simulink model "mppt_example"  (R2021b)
settings: Solver=VariableStepAuto  StartTime=0.0  StopTime=2  FixedStep=1e-5  RelTol=1e-3
libraries: spsSeriesRLCBranchLib x4, spsVoltageMeasurementLib x2, spsControlledCurrentSourceLib x1, spsCurrentMeasurementLib x1, spsDiodeLib x1, spsGroundLib x1, spsIGBTLib x1, simulink x1, spspowerguiLib x1

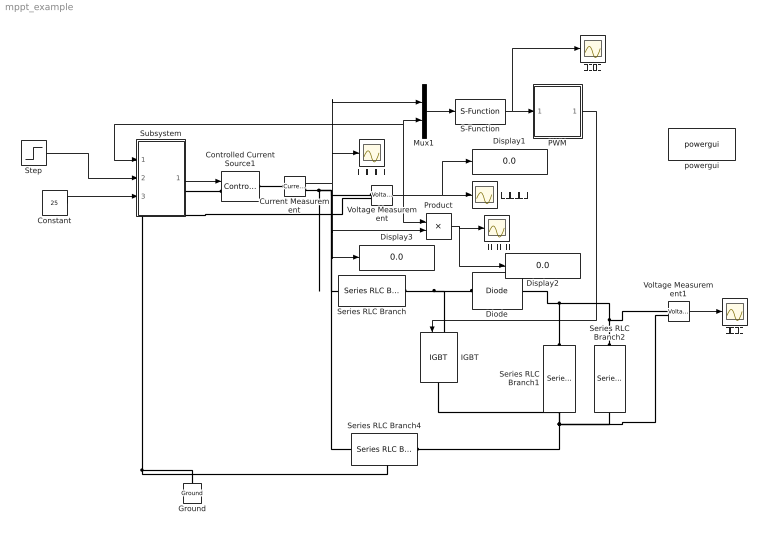
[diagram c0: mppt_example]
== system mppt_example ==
  Constant : Constant  Value=25
  Controlled Current Source1 : spsControlledCurrentSourceLib/Controlled Current Source  Initialize=on  Source_Type=AC  Amplitude=0  Phase=0  Frequency=0  Measurements=None
  Current Measurement : spsCurrentMeasurementLib/Current Measurement  PhasorSimulation=off  OutputType=Complex  PSBequivalent=0
  Diode : spsDiodeLib/Diode  Ron=0.001  Lon=0  Vf=0.8  IC=0  UseSnubber=0  Rs=500  Cs=250e-9  Measurements=off
  Display1 : Display
  Display2 : Display
  Display3 : Display
  Ground : spsGroundLib/Ground  LConnTagsString=a
  IGBT : spsIGBTLib/IGBT  Ron=0.001  Lon=0  Vf=1  Tf=1e-6  Tt=2e-6  IC=0  Rs=1e5  Cs=inf  Measurements=off
  Mux1 : Mux  Inputs=2
  PWM : Subsystem
  Product : Product
  S-Function : S-Function  FunctionName=modbusCom1  SFunctionDeploymentMode=off  EnableBusSupport=off
  Series RLC Branch : spsSeriesRLCBranchLib/Series RLC Branch  LConnTagsString=__new0  RConnTagsString=__new0  BranchType=L  Resistance=0  Inductance=1e-2  SetiL0=off  InitialCurrent=0  Capacitance=0  Setx0=off  InitialVoltage=0  Measurements=None
  Series RLC Branch1 : spsSeriesRLCBranchLib/Series RLC Branch  LConnTagsString=__new0  RConnTagsString=__new0  BranchType=C  Resistance=0  Inductance=0  SetiL0=off  InitialCurrent=0  Capacitance=3e-4  Setx0=off  InitialVoltage=0  Measurements=None
  Series RLC Branch2 : spsSeriesRLCBranchLib/Series RLC Branch  LConnTagsString=__new0  RConnTagsString=__new0  BranchType=R  Resistance=20  Inductance=0  SetiL0=off  InitialCurrent=0  Capacitance=0  Setx0=off  InitialVoltage=0  Measurements=None
  Series RLC Branch4 : spsSeriesRLCBranchLib/Series RLC Branch  LConnTagsString=__new0  RConnTagsString=__new0  BranchType=C  Resistance=0  Inductance=0  SetiL0=off  InitialCurrent=0  Capacitance=1e-4  Setx0=off  InitialVoltage=0  Measurements=None
  Step : Step  Time=0.5  Before=1000  After=1200  SampleTime=0
  Subsystem : Subsystem
  Voltage Measurement : spsVoltageMeasurementLib/Voltage Measurement  PhasorSimulation=off  OutputType=Complex  PSBequivalent=0
  Voltage Measurement1 : spsVoltageMeasurementLib/Voltage Measurement  PhasorSimulation=off  OutputType=Complex  PSBequivalent=0
  powergui : spspowerguiLib/powergui  Priority=1  SimulationMode=Discrete  SampleTime=10e-6  frequency=60  Iterations=50  frequencyindice=0  Pbase=100e6  ErrMax=1e-4  UnitsV=kV  UnitsW=MW  buscounter=0  FunctionMessages=off  echomessages=off  EnableUseOfTLC=off  CurrentSourceSwitches=off  DisableSnubberDevices=off  DisableRonSwitches=off  DisableVfSwitches=off  DisplayEquations=off  AutomaticDiscreteSolvers=off  SolverType=Tustin/Backward Euler (TBE)  Interpol=off  ExternalGateDelay=off  methode=off  Ts=100  x0status=blocks  SPID=on  SwTol=0  HookPort=off  NonlinearTolerance=1e-4  nMaxIteration=100  ContinueOnMaxIteration=off  RestoreLinks=warning  ResistiveCurrentMeasurement=off  Frange=[0:2:500]  Ylog=off  Xlog=on  ShowGrid=off  save=off  variable=ZData  structure=0  ZoomFFT=off  StartTime=0.0  cycles=1  DisplayStyle=1  fundamental=60  FreqAxis=off  MaxFrequency=1000  frequencyindicesteady=1  RmsSteady=1  display=off
  光伏输出功率 : Scope
  光伏输出电压 : Scope
  光伏输出电流 : Scope
  控制输出 : Scope
  负载电压 : Scope
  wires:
  Voltage Measurement/1 -> Mux1/2, Subsystem/1(V), Display1/1, 光伏输出电压/1, Product/1
  PWM/1(D) -> IGBT/1
  Subsystem/1(Out1) -> Controlled Current Source1/1
  Current Measurement/1 -> Product/2, Display3/1, Mux1/1, 光伏输出电流/1
  Product/1 -> Display2/1, 光伏输出功率/1
  S-Function/1 -> 控制输出/1, PWM/1(PWM)
  Constant/1 -> Subsystem/3(T)
  Voltage Measurement1/1 -> 负载电压/1
  Step/1 -> Subsystem/2(S)
  Mux1/1 -> S-Function/1
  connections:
  Series RLC Branch/RConn1 -- IGBT/LConn1 -- Diode/LConn1
  Series RLC Branch1/RConn1 -- Voltage Measurement1/LConn2 -- Voltage Measurement/LConn2 -- Controlled Current Source1/LConn1 -- Ground/LConn1 -- Series RLC Branch4/LConn1 -- Series RLC Branch2/RConn1 -- IGBT/RConn1
  Series RLC Branch2/LConn1 -- Voltage Measurement1/LConn1 -- Diode/RConn1 -- Series RLC Branch1/LConn1
  Voltage Measurement/LConn1 -- Series RLC Branch4/RConn1 -- Series RLC Branch/LConn1 -- Current Measurement/RConn1
  Current Measurement/LConn1 -- Controlled Current Source1/RConn1

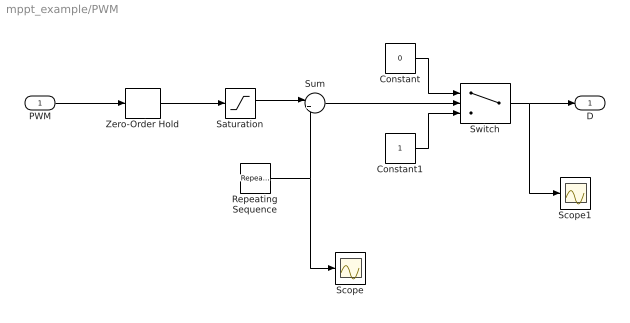
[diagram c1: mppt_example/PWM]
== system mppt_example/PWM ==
  PWM : Inport
  Constant : Constant  Value=0
  Constant1 : Constant
  Repeating Sequence : simulink/Sources/Repeating Sequence  rep_seq_t=[0 0.0005]  rep_seq_y=[-1 1]
  Saturation : Saturate
  Scope : Scope
  Scope1 : Scope
  Sum : Sum  Inputs=|+-
  Switch : Switch  Criteria=u2 > Threshold
  Zero-Order Hold : ZeroOrderHold  SampleTime=0.0001
  D : Outport
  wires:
  Constant1/1 -> Switch/3
  PWM/1 -> Zero-Order Hold/1
  Repeating Sequence/1 -> Scope/1, Sum/2
  Sum/1 -> Switch/2
  Constant/1 -> Switch/1
  Switch/1 -> D/1, Scope1/1
  Saturation/1 -> Sum/1
  Zero-Order Hold/1 -> Saturation/1

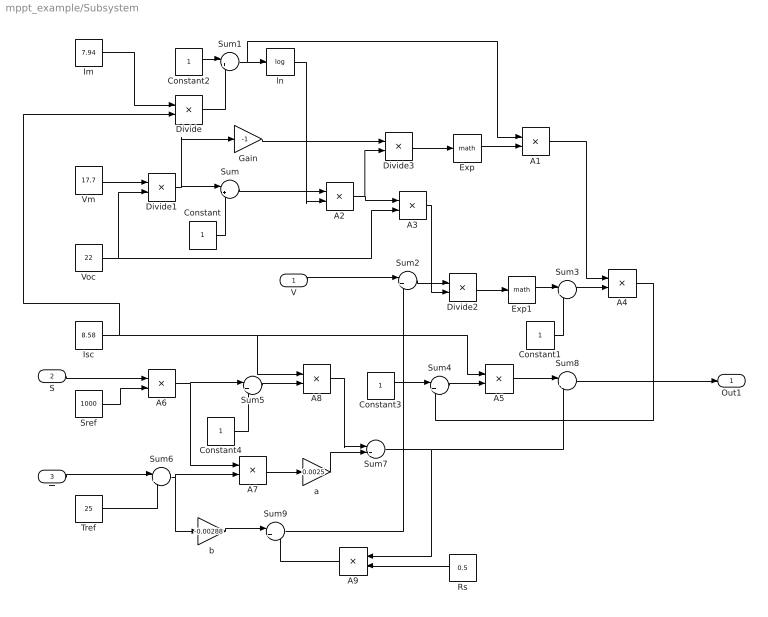
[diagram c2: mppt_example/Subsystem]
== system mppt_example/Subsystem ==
  V : Inport
  S : Inport  Port=2
  T : Inport  Port=3
  A{1,3..5,7..9} (7 alike) : Product
  A2 : Product  Inputs=*/
  A6 : Product  Inputs=*/
  Constant{,1..4} (5 alike) : Constant
  Divide{,1..3} (4 alike) : Product  Inputs=*/
  Exp : Math  SignedPower=on
  Exp1 : Math  SignedPower=on
  Gain : Gain  Gain=-1
  Im : Constant  Value=7.94
  Isc : Constant  Value=8.58
  Rs : Constant  Value=0.5
  Sref : Constant  Value=1000
  Sum{,1..6,9} (8 alike) : Sum  Inputs=|+-
  Sum7 : Sum  Inputs=|++
  Sum8 : Sum  Inputs=|++
  Tref : Constant  Value=25
  Vm : Constant  Value=17.7
  Voc : Constant  Value=22
  a : Gain  Gain=0.0025
  b : Gain  Gain=-0.00288
  ln : Math  Operator=log  SignedPower=on
  Out1 : Outport
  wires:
  Isc/1 -> A8/1, A5/1, Divide/2
  Sum8/1 -> Out1/1
  A9/1 -> Sum9/2
  Constant2/1 -> Sum1/1
  b/1 -> Sum9/1
  Constant/1 -> Sum/2
  Divide3/1 -> Exp/1
  Vm/1 -> Divide1/1
  Voc/1 -> A3/2, Divide1/2
  ln/1 -> A2/2
  Rs/1 -> A9/2
  Gain/1 -> Divide3/1
  Sum7/1 -> A9/1, Sum8/2
  Divide/1 -> Sum1/2
  Sum1/1 -> A1/1, ln/1
  A5/1 -> Sum8/1
  A8/1 -> Sum7/1
  Im/1 -> Divide/1
  Sum6/1 -> b/1, A7/2
  Exp/1 -> A1/2
  Divide1/1 -> Sum/1, Gain/1
  Sum5/1 -> A8/2
  V/1 -> Sum2/1
  Sum3/1 -> A4/2
  Sum2/1 -> Divide2/1
  Exp1/1 -> Sum3/1
  Divide2/1 -> Exp1/1
  A1/1 -> A4/1
  A4/1 -> Sum4/2
  Sum4/1 -> A5/2
  S/1 -> A6/1
  Sref/1 -> A6/2
  A2/1 -> A3/1, Divide3/2
  A3/1 -> Divide2/2
  Constant4/1 -> Sum5/2
  Constant3/1 -> Sum4/1
  Tref/1 -> Sum6/2
  A7/1 -> a/1
  a/1 -> Sum7/2
  Sum/1 -> A2/1
  T/1 -> Sum6/1
  Constant1/1 -> Sum3/2
  A6/1 -> A7/1, Sum5/1
  Sum9/1 -> Sum2/2
